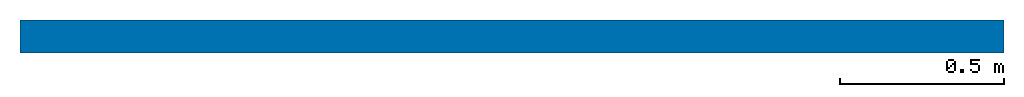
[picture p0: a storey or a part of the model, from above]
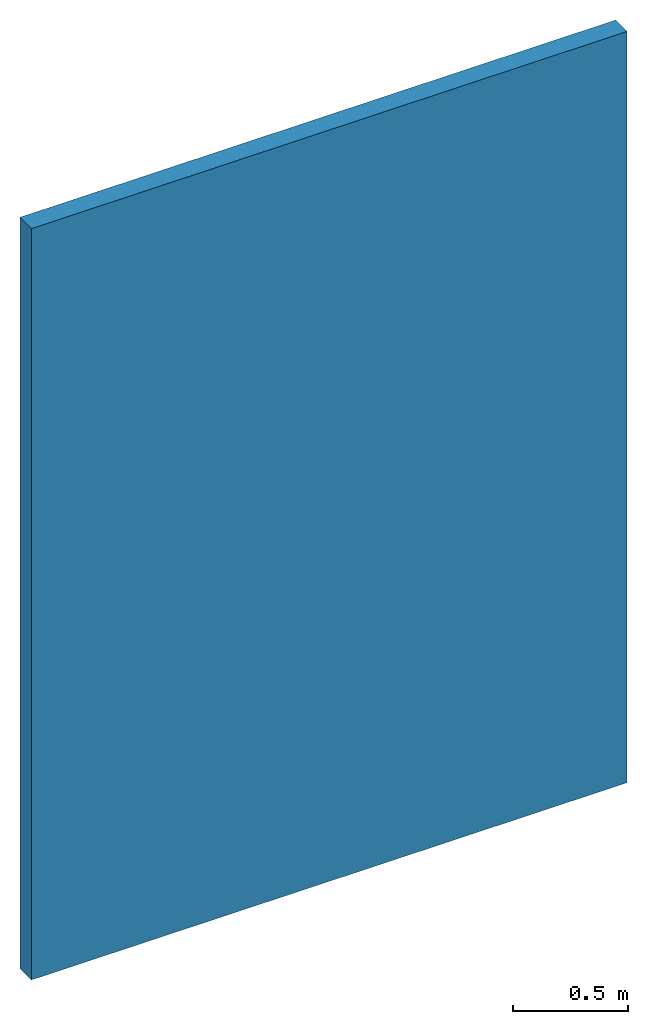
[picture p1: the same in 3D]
Properties of the parts of a building model (IFC2X3)

# File
Description: ViewDefinition [CoordinationView_V2.0, QuantityTakeOffAddOnView]
File name: 0001
Time: 2018-04-04T18:10:48
Written by: The EXPRESS Data Manager Version 5.02.0100.07 : 28 Aug 2013
Made in: 20170419_0315(x64) - Exporter 17.0.1128.0 - Альтернативный интерфейс 17.17.0.0
Comment: STEP Physical File produced by: The EXPRESS Data Manager Version 5.02.0100.07 : 28 Aug 2013 * Module: EDMstepFileFactory/EDMstandAlone * Creation date: Wed Apr 04 18:10:48 2018 * Host: w13mim038 * Database: C:\Users\odegov.s\AppData\Local\Temp\{CDFF85E9-1302-4167-911C-1FFEC902F534}\ifc * Database version: 5507 * Database creation date: Wed Apr 04 18:10:48 2018 * Schema: IFC2X3 * Model: DataRepository.ifc * Model creation date: Wed Apr 04 18:10:48 2018 * Header model: DataRepository.ifc_HeaderModel * Header model creation date: Wed Apr 04 18:10:48 2018 * EDMuser: sdai-user * EDMgroup: sdai-group * License ID and type: 5605 : Permanent license. Expiry date: * EDMstepFileFactory options: 020000

# IfcProject, 0001
LongName: Наименование проекта; Phase: Статус проекта

# IfcSite, Default
RefLatitude: 55, 44, 59, 999999; RefLongitude: 37, 42, 0, 2746; RefElevation: 0 mm
Прочее - Адрес проекта: Укажите адрес; Дата утверждения проекта: Дата выпуска; Заказчик: Владелец; Категория: Сведения о проекте; Наименование проекта: Наименование проекта; Номер проекта: 0001; Статус проекта: Статус проекта

# IfcBuilding
Pset_BuildingCommon - NumberOfStoreys: 1
Прочее - Категория: Сведения о проекте; Адрес проекта: Укажите адрес; Дата утверждения проекта: Дата выпуска; Заказчик: Владелец; Наименование проекта: Наименование проекта; Номер проекта: 0001; Статус проекта: Статус проекта

# IfcBuildingStorey, Уровень 1
LongName: Уровень 1; Elevation: 0 mm
Прочее - Категория: Уровни; Имя семейства: Уровень; Код типа: Уровень: Верхний брус 8 мм; Семейство: Уровень: Верхний брус 8 мм; Семейство и типоразмер: Уровень: Верхний брус 8 мм; Тип: Уровень: Верхний брус 8 мм
Зависимости - Фасад: 0 mm; Базовая отметка: Базовая точка проекта
Идентификация - Несущие конструкции: no; Имя: Уровень 1; Построение этажа: yes; Имя типа: Верхний брус 8 мм
Размеры - Расчетная высота: 0 mm
Графика - Вес линий: 1; Обозначение: Заголовок уровня - Окружность: Заголовок уровня - Окружность; Образец линий: Центр; Стандартное обозначение второго конца: yes; Стандартное обозначение первого конца: no; Цвет: 0

# IfcWallStandardCase: Базовая стена:Облицовка КНАУФ С666 Применение внутри здания ПC75/50 ПН75х40 шаг 600 ГВЛВ 12.5, Базовая стена:Облицовка КНАУФ С666 Применение внутри здания ПC75/50 ПН75х40 шаг 600 ГВЛВ 12.5:421415
In: Уровень 1
Type - PredefinedType: STANDARD; Material: КНАУФ-суперлист 12.5 mm, КНАУФ-суперлист 12.5 mm, Luft 25 mm, КНАУФ-профиль+мин.вата 50@600mm 50 mm
Type - Графика - Цвет штриховки при низкой детализации: 0
Type - Идентификация - Имя типа: Облицовка КНАУФ С666 Применение внутри здания ПC75/50 ПН75х40 шаг 600 ГВЛВ 12.5
Type - Материалы и отделка - Материал несущих конструкций: КНАУФ-профиль+мин.вата 50@600mm
Type - Прочее - Категория: Стены; Имя семейства: Базовая стена
Type - Свойства аналитической модели - Коэффициент поглощения: 0.7; Коэффициент теплопередачи (U): 0.40678; Теплоемкость: 29530.1; Термостойкость: 2.45833; Шероховатость: 3
Type - Строительство - Винт MN 30: 6; Винт MN 40: 14; Грунтовка: 0,1; Дюбель: 1,6; КНАУФ-Гипсоволокнистый лист влагостойкий ГВЛВ: 2; Кронштейн: 0,7; Лента армирующая: 0,75; Лента уплотнительная 70х3,2: 1,3; Огибание в местах вставки элементов: Нет; Огибание в торцах стен: Нет; Подвес прямой для ПП 60/27: 2.3; Профиль направляющий ПН75/40: 0,7; Профиль стоечный ПС75/50: 2; Функция: Внутренние слои; Ширина: 100 mm; Шпаклевка КНАУФ-Фуген: 0,5
BaseQuantities - Height: 4000 mm; Length: 3000 mm; Width: 100 mm; GrossFootprintArea: 0.3 m2; GrossSideArea: 12 m2; GrossVolume: 1.2 m3
Зависимости - Базовая зависимость: Уровень: Уровень 1; Граница помещения: yes; Линия привязки: Осевая линия стены; Неприсоединенная высота: 4000 mm; Примыкание сверху: no; Примыкание снизу: no; Размер выступа сверху: 0 mm; Размер выступа снизу: 0 mm; Связь с формообразующим элементом: no; Смещение сверху: 0 mm; Смещение снизу: 0 mm
Несущие конструкции - Включить аналитическую модель: no; Использование в конструкции: Ненесущая; Несущие конструкции: no
Прочее - Код типа: Базовая стена: Облицовка КНАУФ С666 Применение внутри здания ПC75/50 ПН75х40 шаг 600 ГВЛВ 12.5; Семейство: Базовая стена: Облицовка КНАУФ С666 Применение внутри здания ПC75/50 ПН75х40 шаг 600 ГВЛВ 12.5; Семейство и типоразмер: Базовая стена: Облицовка КНАУФ С666 Применение внутри здания ПC75/50 ПН75х40 шаг 600 ГВЛВ 12.5; Тип: Базовая стена: Облицовка КНАУФ С666 Применение внутри здания ПC75/50 ПН75х40 шаг 600 ГВЛВ 12.5
Размеры - Длина: 3000 mm; Объем: 1.2 m3; Площадь: 12 m2
Стадии - Стадия возведения: Новая конструкция
Pset_WallCommon - Reference: Облицовка КНАУФ С666 Применение внутри здания ПC75/50 ПН75х40 шаг 600 ГВЛВ 12.5; LoadBearing: no; ExtendToStructure: no; IsExternal: no; ThermalTransmittance: 0.40678 kg/K/s3
